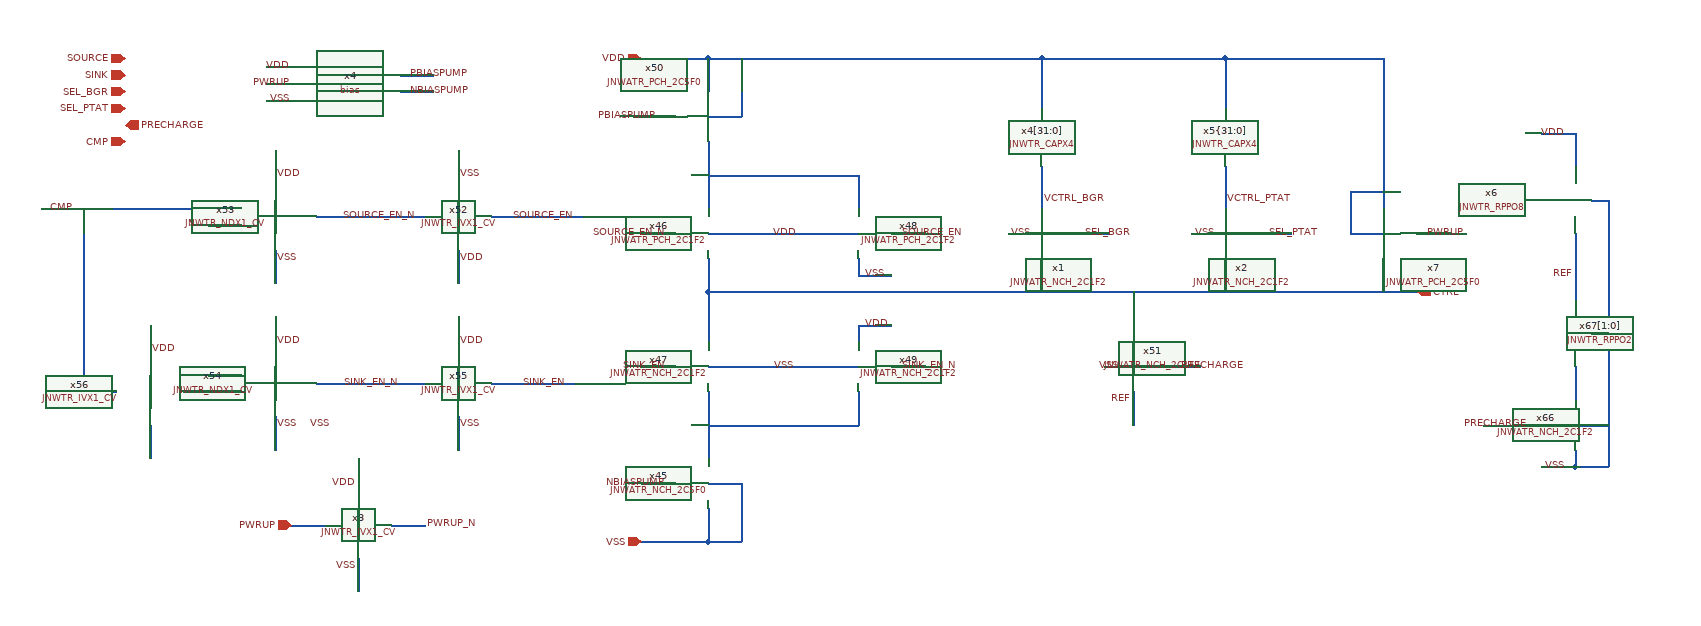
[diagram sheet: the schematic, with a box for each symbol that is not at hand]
v {xschem version=3.4.6 file_version=1.2}
G {}
K {}
V {}
S {}
E {}
N 2020 -490 2020 -470 {
lab=VSS}
N 1910 -520 1980 -520 {
lab=PRECHARGE}
N 1980 -470 2020 -470 {
lab=VSS}
N 2020 -470 2060 -470 {
lab=VSS}
N 2020 -870 2020 -830 {
lab=VDD}
N 1980 -870 2020 -870 {
lab=VDD}
N 2060 -790 2060 -470 {
lab=VSS}
N 2020 -750 2020 -710 {lab=REF}
N 980 -420 980 -380 {
lab=VSS}
N 890 -890 940 -890 {
lab=PBIASPUMP}
N 900 -450 940 -450 {
lab=NBIASPUMP}
N 1160 -720 1160 -700 {
lab=VSS}
N 1160 -700 1200 -700 {
lab=VSS}
N 1160 -640 1160 -620 {
lab=VDD}
N 1160 -640 1200 -640 {
lab=VDD}
N 1200 -590 1240 -590 {
lab=SINK_EN_N}
N 900 -380 980 -380 {
lab=VSS}
N 980 -560 980 -480 {
lab=#net3}
N 1160 -560 1160 -520 {
lab=#net3}
N 980 -520 1160 -520 {
lab=#net3}
N 1530 -590 1570 -590 {
lab=PRECHARGE}
N 1455 -590 1490 -590 {
lab=VSS}
N 1490 -680 1490 -620 {
lab=CTRL}
N 380 -760 420 -760 {lab=SOURCE}
N 980 -720 980 -680 {
lab=CTRL}
N 980 -680 980 -620 {lab=CTRL}
N 980 -960 1380 -960 {lab=VDD}
N 900 -960 980 -960 {lab=VDD}
N 510 -770 640 -770 {lab=SOURCE_EN_N}
N 720 -770 830 -770 {lab=SOURCE_EN}
N 180 -780 420 -780 {lab=CMP}
N 230 -780 230 -560 {lab=CMP}
N 380 -580 420 -580 {lab=SINK}
N 980 -590 1160 -590 {lab=VSS}
N 900 -750 940 -750 {lab=SOURCE_EN_N}
N 980 -750 1160 -750 {lab=VDD}
N 230 -560 270 -560 {lab=CMP}
N 350 -560 420 -560 {lab=#net4}
N 510 -570 640 -570 {lab=SINK_EN_N}
N 1490 -560 1490 -520 {lab=REF}
N 1380 -830 1380 -780 {lab=VCTRL_BGR}
N 1380 -960 1600 -960 {lab=VDD}
N 1640 -750 1680 -750 {lab=SEL_PTAT}
N 1420 -750 1460 -750 {lab=SEL_BGR}
N 480 -400 520 -400 {lab=PWRUP}
N 600 -400 640 -400 {lab=PWRUP_N}
N 1790 -720 1790 -680 {lab=CTRL}
N 1790 -960 1790 -780 {lab=VDD}
N 460 -530 460 -490 {lab=VSS}
N 460 -650 460 -610 {lab=VDD}
N 310 -640 310 -600 {lab=VDD}
N 310 -520 310 -480 {lab=#net5}
N 720 -570 820 -570 {lab=SINK_EN}
N 980 -450 1020 -450 {lab=VSS}
N 1020 -450 1020 -380 {lab=VSS}
N 980 -380 1020 -380 {lab=VSS}
N 680 -530 680 -490 {lab=VSS}
N 680 -650 680 -610 {lab=VDD}
N 460 -730 460 -690 {lab=VSS}
N 460 -850 460 -810 {lab=VDD}
N 680 -850 680 -810 {lab=VSS}
N 680 -730 680 -690 {lab=VDD}
N 560 -360 560 -320 {lab=VSS}
N 560 -480 560 -440 {lab=VDD}
N 1750 -750 1790 -750 {lab=VDD}
N 1750 -800 1750 -750 {lab=VDD}
N 1750 -800 1790 -800 {lab=VDD}
N 900 -590 940 -590 {lab=SINK_EN}
N 980 -960 980 -920 {lab=VDD}
N 980 -890 1020 -890 {lab=VDD}
N 1340 -750 1380 -750 {lab=VSS}
N 1560 -750 1600 -750 {lab=VSS}
N 980 -680 1830 -680 {lab=CTRL}
N 1380 -720 1380 -680 {lab=CTRL}
N 1600 -720 1600 -680 {lab=CTRL}
N 1600 -830 1600 -780 {lab=VCTRL_PTAT}
N 1160 -820 1160 -780 {lab=#net6}
N 980 -820 1160 -820 {lab=#net6}
N 980 -860 980 -780 {lab=#net6}
N 1020 -960 1020 -890 {lab=VDD}
N 1380 -960 1380 -900 {lab=VDD}
N 1600 -960 1600 -900 {lab=VDD}
N 1600 -960 1790 -960 {lab=VDD}
N 2040 -790 2060 -790 {lab=VSS}
N 2040 -630 2060 -630 {lab=VSS}
N 2020 -520 2040 -520 {lab=VSS}
N 2040 -520 2060 -520 {lab=VSS}
N 2020 -710 2020 -670 {lab=REF}
N 2020 -590 2020 -550 {lab=#net7}
N 450 -950 490 -950 {lab=VDD}
N 450 -930 490 -930 {lab=PWRUP}
N 450 -910 490 -910 {lab=VSS}
N 610 -940 650 -940 {lab=PBIASPUMP}
N 610 -920 650 -920 {lab=NBIASPUMP}
N 1200 -750 1240 -750 {lab=SOURCE_EN}
N 1830 -750 1870 -750 {lab=PWRUP}
C {JNW_ATR_SKY130A/JNWATR_NCH_2C1F2.sym} 1980 -520 0 0 {name=x66 }
C {devices/lab_wire.sym} 1965 -520 0 0 {name=p125 sig_type=std_logic lab=PRECHARGE}
C {JNW_TR_SKY130A/JNWTR_RPPO2.sym} 2020 -670 3 1 {name=x67[1:0]}
C {devices/ipin.sym} 280 -940 0 0 {name=p128 lab=SINK
}
C {devices/ipin.sym} 280 -960 0 0 {name=p129 lab=SOURCE}
C {devices/ipin.sym} 900 -960 0 0 {name=p94 lab=VDD}
C {devices/opin.sym} 1830 -680 0 0 {name=p95 lab=CTRL}
C {devices/ipin.sym} 900 -380 0 0 {name=p96 lab=VSS
}
C {devices/ipin.sym} 280 -880 2 1 {name=p97 lab=PRECHARGE
}
C {JNW_ATR_SKY130A/JNWATR_NCH_2C5F0.sym} 940 -450 0 0 {name=x45 }
C {devices/lab_wire.sym} 1055 -750 0 1 {name=p98 sig_type=std_logic lab=VDD}
C {JNW_ATR_SKY130A/JNWATR_PCH_2C1F2.sym} 940 -750 0 0 {name=x46 }
C {JNW_ATR_SKY130A/JNWATR_NCH_2C1F2.sym} 940 -590 0 0 {name=x47 }
C {JNW_ATR_SKY130A/JNWATR_PCH_2C1F2.sym} 1200 -750 0 1 {name=x48 }
C {devices/lab_wire.sym} 1165 -700 0 1 {name=p99 sig_type=std_logic lab=VSS}
C {JNW_ATR_SKY130A/JNWATR_NCH_2C1F2.sym} 1200 -590 0 1 {name=x49 }
C {devices/lab_wire.sym} 1085 -590 2 1 {name=p100 sig_type=std_logic lab=VSS}
C {JNW_ATR_SKY130A/JNWATR_PCH_2C5F0.sym} 940 -890 0 0 {name=x50 }
C {devices/lab_wire.sym} 1165 -640 0 1 {name=p102 sig_type=std_logic lab=VDD}
C {JNW_ATR_SKY130A/JNWATR_NCH_2C1F2.sym} 1530 -590 0 1 {name=x51 }
C {devices/lab_wire.sym} 1475 -590 0 0 {name=p103 sig_type=std_logic lab=VSS}
C {devices/lab_wire.sym} 920 -890 0 0 {name=p107 sig_type=std_logic lab=PBIASPUMP}
C {devices/lab_wire.sym} 930 -450 0 0 {name=p108 sig_type=std_logic lab=NBIASPUMP}
C {devices/ipin.sym} 280 -860 0 0 {name=p112 lab=CMP}
C {JNW_TR_SKY130A/JNWTR_IVX1_CV.sym} 640 -770 2 1 {name=x52 }
C {devices/lab_wire.sym} 410 -760 2 1 {name=p156 sig_type=std_logic lab=SOURCE

}
C {devices/lab_wire.sym} 680 -720 2 0 {name=p169 sig_type=std_logic lab=VDD

}
C {devices/lab_wire.sym} 680 -820 0 1 {name=p170 sig_type=std_logic lab=VSS

}
C {devices/lab_wire.sym} 460 -820 0 1 {name=p104 sig_type=std_logic lab=VDD

}
C {JNW_TR_SKY130A/JNWTR_NDX1_CV.sym} 420 -760 0 0 {name=x53 }
C {devices/lab_wire.sym} 460 -720 2 0 {name=p105 sig_type=std_logic lab=VSS

}
C {devices/lab_wire.sym} 460 -620 0 1 {name=p132 sig_type=std_logic lab=VDD

}
C {devices/lab_wire.sym} 460 -520 2 0 {name=p133 sig_type=std_logic lab=VSS

}
C {devices/lab_wire.sym} 410 -580 0 0 {name=p157 sig_type=std_logic lab=SINK

}
C {JNW_TR_SKY130A/JNWTR_IVX1_CV.sym} 640 -570 0 0 {name=x55 }
C {devices/lab_wire.sym} 680 -620 0 1 {name=p158 sig_type=std_logic lab=VDD

}
C {devices/lab_wire.sym} 680 -520 2 0 {name=p159 sig_type=std_logic lab=VSS

}
C {JNW_TR_SKY130A/JNWTR_IVX1_CV.sym} 270 -560 0 0 {name=x56 }
C {devices/lab_wire.sym} 310 -610 0 1 {name=p160 sig_type=std_logic lab=VDD

}
C {devices/lab_wire.sym} 500 -520 2 0 {name=p161 sig_type=std_logic lab=VSS

}
C {JNW_TR_SKY130A/JNWTR_NDX1_CV.sym} 420 -560 0 0 {name=x54 }
C {devices/lab_wire.sym} 1430 -750 0 1 {name=p171 sig_type=std_logic lab=SEL_BGR

}
C {devices/lab_wire.sym} 1650 -750 0 1 {name=p183 sig_type=std_logic lab=SEL_PTAT

}
C {devices/lab_wire.sym} 1600 -790 0 1 {name=p184 sig_type=std_logic lab=VCTRL_PTAT

}
C {devices/lab_wire.sym} 1380 -790 0 1 {name=p185 sig_type=std_logic lab=VCTRL_BGR

}
C {devices/ipin.sym} 280 -900 0 0 {name=p1 lab=SEL_PTAT
}
C {devices/ipin.sym} 280 -920 0 0 {name=p2 lab=SEL_BGR}
C {devices/lab_wire.sym} 1370 -750 2 1 {name=p4 sig_type=std_logic lab=VSS

}
C {JNW_ATR_SKY130A/JNWATR_NCH_2C1F2.sym} 1420 -750 0 1 {name=x1 }
C {devices/lab_wire.sym} 1590 -750 2 1 {name=p7 sig_type=std_logic lab=VSS

}
C {JNW_ATR_SKY130A/JNWATR_NCH_2C1F2.sym} 1640 -750 0 1 {name=x2 }
C {devices/ipin.sym} 480 -400 0 0 {name=p3 lab=PWRUP
}
C {JNW_TR_SKY130A/JNWTR_IVX1_CV.sym} 520 -400 0 0 {name=x3 }
C {devices/lab_wire.sym} 560 -350 2 1 {name=p10 sig_type=std_logic lab=VSS}
C {devices/lab_wire.sym} 560 -450 0 0 {name=p11 sig_type=std_logic lab=VDD}
C {JNW_ATR_SKY130A/JNWATR_PCH_2C5F0.sym} 1830 -750 0 1 {name=x7 }
C {devices/lab_wire.sym} 1840 -750 0 1 {name=p13 sig_type=std_logic lab=PWRUP}
C {devices/lab_pin.sym} 640 -400 0 1 {name=p5 sig_type=std_logic lab=PWRUP_N}
C {JNW_TR_SKY130A/JNWTR_CAPX4.sym} 1380 -840 0 0 {name=x4[31:0]}
C {JNW_TR_SKY130A/JNWTR_CAPX4.sym} 1600 -840 0 0 {name=x5\{31:0]}
C {devices/lab_wire.sym} 1545 -590 0 1 {name=p12 sig_type=std_logic lab=PRECHARGE}
C {LELO_TORD_SKY130A/bias.sym} 550 -930 0 0 {name=x4}
C {devices/lab_wire.sym} 480 -950 0 0 {name=p14 sig_type=std_logic lab=VDD}
C {devices/lab_wire.sym} 480 -910 0 0 {name=p15 sig_type=std_logic lab=VSS}
C {devices/lab_wire.sym} 480 -930 0 0 {name=p16 sig_type=std_logic lab=PWRUP}
C {devices/lab_wire.sym} 620 -920 0 1 {name=p17 sig_type=std_logic lab=NBIASPUMP}
C {devices/lab_wire.sym} 620 -940 0 1 {name=p18 sig_type=std_logic lab=PBIASPUMP}
C {devices/lab_wire.sym} 630 -770 2 1 {name=p20 sig_type=std_logic lab=SOURCE_EN_N}
C {devices/lab_wire.sym} 610 -570 0 0 {name=p21 sig_type=std_logic lab=SINK_EN_N}
C {devices/lab_wire.sym} 810 -570 0 0 {name=p22 sig_type=std_logic lab=SINK_EN}
C {devices/lab_wire.sym} 820 -770 2 1 {name=p23 sig_type=std_logic lab=SOURCE_EN}
C {devices/lab_wire.sym} 930 -590 0 0 {name=p8 sig_type=std_logic lab=SINK_EN}
C {devices/lab_wire.sym} 930 -750 2 1 {name=p6 sig_type=std_logic lab=SOURCE_EN_N}
C {devices/lab_wire.sym} 1210 -750 2 0 {name=p24 sig_type=std_logic lab=SOURCE_EN}
C {devices/lab_wire.sym} 1210 -590 0 1 {name=p19 sig_type=std_logic lab=SINK_EN_N}
C {devices/lab_wire.sym} 220 -780 0 0 {name=p25 sig_type=std_logic lab=CMP

}
C {devices/lab_wire.sym} 2010 -470 0 0 {name=p9 sig_type=std_logic lab=VSS

}
C {devices/lab_wire.sym} 2020 -700 0 0 {name=p26 sig_type=std_logic lab=REF

}
C {devices/lab_wire.sym} 2010 -870 0 0 {name=p27 sig_type=std_logic lab=VDD

}
C {devices/lab_wire.sym} 1490 -550 2 1 {name=p28 sig_type=std_logic lab=REF

}
C {JNW_TR_SKY130A/JNWTR_RPPO8.sym} 2020 -750 3 0 {name=x6 }
